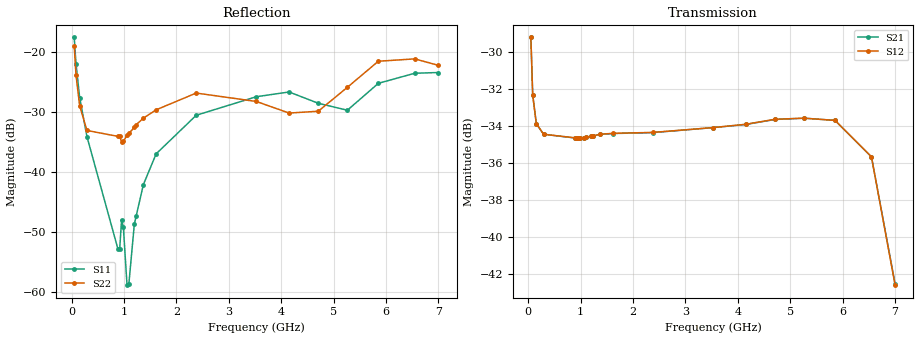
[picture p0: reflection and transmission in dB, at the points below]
! Integrated Device Technology
! Corporate Headquarters
! 6024 Silver Creek Valley Road
! San Jose, CA 95138  USA
! Phone:  1-408-284-8200
! Toll Free:  1-800-223-1366
! Webpage:  http://www.idt.com/
! Timing and RF Division
! 515 Groton Road, Suite 102
! Westford, MA 01886-6024
! Device:  F2258
! Description: Voltage Variable RF Attenuator
! Frequency:  50.0 -  6000.00 MHz
! Package:  3x3 mm Thin QFN Plastic Package: 16 pin
! Ports:  2 RF, 2 DC
!  Pin  1  = NC
!  Pin  2  = NC
!  Pin  3  = RF2  = Port 2
!  Pin  4  = GND
!  Pin  5  = Vdd
!  Pin  6  = NC
!  Pin  7  = VCTRL
!  Pin  8  = NC
!  Pin  9  = GND
!  Pin 10  = RF1  = Port 1
!  Pin 11  = NC
!  Pin 12  = NC
!  Pin 13  = NC
!  Pin 14  = NC
!  Pin 15  = NC
!  Pin 16  = NC
! Vcntrl:  1.920 Volts
! Vdd:  +3.300 Volts
! Current:  1.158 mA
! Data:  The device was measured on a the F2258 evaluation board which has
!  individual transmission lines to the RF pins.  Data was collected
!  using a calibrated network analyzer.  The evaluation board was
!  de-embedded using a TRL calibration technique.
!  The reference plane is the edge of the package pin.
! Misc:  SN 10
!  Action Tracker AT0285
! Date Measured:  2014-12-10
! Date:  2016-01-13  MJV
! Note:
!  Integrated Device Technology supplies this data as a sample of measured
!  data at the package pin for this product.  Your particular data for this
!  product may vary.
!  Data was taken at 25 degrees C.
!  Integrated Device Technology reserves the right to change this data at anytime.
!Freq_(GHz)  S11M_(dB)  S11P_(deg)  S21M_(dB)  S21P_(deg)  S12M_(dB)  S12P_(deg)  S22M_(dB)  S22P_(deg)
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# GHz S dB R 50
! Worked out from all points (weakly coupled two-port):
!   201 points, 50 MHz to 7 GHz, reference 50 ohm
!   highest |S21| = -29.19 dB at 50 MHz (marker M1); lowest = -42.5 dB at 7 GHz (marker M2)
!   lowest |S11| = -58.8 dB at 1.058 GHz (marker M3), VSWR 1.00, Z = 49.9 + j0.0522 ohm
!   |S11| at or under -10 dB: start of sweep to end of sweep
!   |S22| runs from -35.0 to -19.0 dB; largest |S21 - S12| = 7.7e-05
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0.05  -17.55 -110.9  -29.19 -65.2  -29.19 -65.1  -19.01 -104.9
0.08475  -21.97 -107.3  -32.29 -45.9  -32.30 -45.9  -23.88 -91.1
0.15425  -27.56 -107.7  -33.86 -27.8  -33.86 -27.8  -28.95 -72.6
0.29325  -34.08 -112.7  -34.43 -16.1  -34.43 -16.1  -33.05 -43.1
0.884  -52.77 166.8  -34.63 -8.8  -34.62 -8.8  -34.03 3.0
0.91875  -52.72 149.2  -34.63 -8.8  -34.62 -8.8  -34.02 3.7
0.9535  -47.94 -161.1  -34.64 -8.8  -34.63 -8.7  -34.99 11.7
0.98825  -49.17 -173.3  -34.63 -8.7  -34.62 -8.7  -34.85 10.3
1.05775  -58.80 152.9  -34.61 -8.6  -34.61 -8.6  -33.88 11.1
1.0925  -58.65 114.4  -34.60 -8.6  -34.58 -8.6  -33.55 11.0
1.19675  -48.70 54.4  -34.55 -8.8  -34.55 -8.8  -32.54 11.4
1.2315  -47.32 44.1  -34.53 -8.7  -34.52 -8.8  -32.10 10.7
1.3705  -42.05 35.8  -34.44 -9.3  -34.43 -9.3  -31.00 11.3
1.61375  -36.94 32.2  -34.39 -10.7  -34.38 -10.7  -29.61 10.5
2.37825  -30.52 47.8  -34.34 -14.7  -34.33 -14.7  -26.82 13.5
3.525  -27.43 91.5  -34.07 -21.7  -34.07 -21.7  -28.22 37.1
4.1505  -26.64 104.9  -33.90 -26.4  -33.89 -26.4  -30.15 46.3
4.7065  -28.52 95.5  -33.63 -31.2  -33.62 -31.2  -29.85 26.9
5.2625  -29.68 54.1  -33.56 -37.3  -33.56 -37.3  -25.86 -4.1
5.85325  -25.20 29.7  -33.68 -47.5  -33.68 -47.5  -21.52 -17.4
6.54825  -23.52 44.9  -35.65 -67.0  -35.65 -67.1  -21.13 -49.5
7  -23.40 84.4  -42.53 -63.3  -42.59 -62.8  -22.21 -126.4
